VERSION 5.7 ;
  NOWIREEXTENSIONATPIN ON ;
  DIVIDERCHAR "/" ;
  BUSBITCHARS "[]" ;
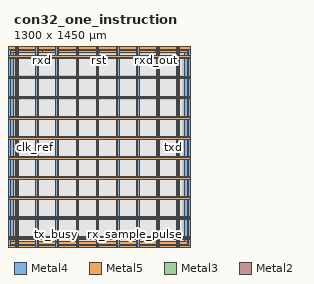
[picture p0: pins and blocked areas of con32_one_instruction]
MACRO con32_one_instruction
  CLASS BLOCK ;
  FOREIGN con32_one_instruction ;
  ORIGIN 0.000 0.000 ;
  SIZE 1300.000 BY 1450.000 ;
  PIN VDD
    DIRECTION INOUT ;
    USE POWER ;
    PORT
      LAYER Metal4 ;
        RECT -24.880 -18.160 -4.880 1464.640 ;
    END
    PORT
      LAYER Metal4 ;
        RECT 1304.640 -18.160 1324.640 1464.640 ;
    END
    PORT
      LAYER Metal5 ;
        RECT -24.880 -18.160 1324.640 1.840 ;
    END
    PORT
      LAYER Metal5 ;
        RECT -24.880 1444.640 1324.640 1464.640 ;
    END
    PORT
      LAYER Metal4 ;
        RECT 12.440 -42.960 22.440 1489.440 ;
    END
    PORT
      LAYER Metal4 ;
        RECT 166.040 -42.960 176.040 1489.440 ;
    END
    PORT
      LAYER Metal4 ;
        RECT 319.640 -42.960 329.640 1489.440 ;
    END
    PORT
      LAYER Metal4 ;
        RECT 473.240 -42.960 483.240 1489.440 ;
    END
    PORT
      LAYER Metal4 ;
        RECT 626.840 -42.960 636.840 1489.440 ;
    END
    PORT
      LAYER Metal4 ;
        RECT 780.440 -42.960 790.440 1489.440 ;
    END
    PORT
      LAYER Metal4 ;
        RECT 934.040 -42.960 944.040 1489.440 ;
    END
    PORT
      LAYER Metal4 ;
        RECT 1087.640 -42.960 1097.640 1489.440 ;
    END
    PORT
      LAYER Metal4 ;
        RECT 1241.240 -42.960 1251.240 1489.440 ;
    END
    PORT
      LAYER Metal5 ;
        RECT -49.680 19.490 1349.440 29.490 ;
    END
    PORT
      LAYER Metal5 ;
        RECT -49.680 172.670 1349.440 182.670 ;
    END
    PORT
      LAYER Metal5 ;
        RECT -49.680 325.850 1349.440 335.850 ;
    END
    PORT
      LAYER Metal5 ;
        RECT -49.680 479.030 1349.440 489.030 ;
    END
    PORT
      LAYER Metal5 ;
        RECT -49.680 632.210 1349.440 642.210 ;
    END
    PORT
      LAYER Metal5 ;
        RECT -49.680 785.390 1349.440 795.390 ;
    END
    PORT
      LAYER Metal5 ;
        RECT -49.680 938.570 1349.440 948.570 ;
    END
    PORT
      LAYER Metal5 ;
        RECT -49.680 1091.750 1349.440 1101.750 ;
    END
    PORT
      LAYER Metal5 ;
        RECT -49.680 1244.930 1349.440 1254.930 ;
    END
    PORT
      LAYER Metal5 ;
        RECT -49.680 1398.110 1349.440 1408.110 ;
    END
  END VDD
  PIN VSS
    DIRECTION INOUT ;
    USE GROUND ;
    PORT
      LAYER Metal4 ;
        RECT -49.680 -42.960 -29.680 1489.440 ;
    END
    PORT
      LAYER Metal4 ;
        RECT 1329.440 -42.960 1349.440 1489.440 ;
    END
    PORT
      LAYER Metal5 ;
        RECT -49.680 -42.960 1349.440 -22.960 ;
    END
    PORT
      LAYER Metal5 ;
        RECT -49.680 1469.440 1349.440 1489.440 ;
    END
    PORT
      LAYER Metal4 ;
        RECT 24.140 -42.960 34.140 1489.440 ;
    END
    PORT
      LAYER Metal4 ;
        RECT 177.740 -42.960 187.740 1489.440 ;
    END
    PORT
      LAYER Metal4 ;
        RECT 331.340 -42.960 341.340 1489.440 ;
    END
    PORT
      LAYER Metal4 ;
        RECT 484.940 -42.960 494.940 1489.440 ;
    END
    PORT
      LAYER Metal4 ;
        RECT 638.540 -42.960 648.540 1489.440 ;
    END
    PORT
      LAYER Metal4 ;
        RECT 792.140 -42.960 802.140 1489.440 ;
    END
    PORT
      LAYER Metal4 ;
        RECT 945.740 -42.960 955.740 1489.440 ;
    END
    PORT
      LAYER Metal4 ;
        RECT 1099.340 -42.960 1109.340 1489.440 ;
    END
    PORT
      LAYER Metal4 ;
        RECT 1252.940 -42.960 1262.940 1489.440 ;
    END
    PORT
      LAYER Metal5 ;
        RECT -49.680 31.190 1349.440 41.190 ;
    END
    PORT
      LAYER Metal5 ;
        RECT -49.680 184.370 1349.440 194.370 ;
    END
    PORT
      LAYER Metal5 ;
        RECT -49.680 337.550 1349.440 347.550 ;
    END
    PORT
      LAYER Metal5 ;
        RECT -49.680 490.730 1349.440 500.730 ;
    END
    PORT
      LAYER Metal5 ;
        RECT -49.680 643.910 1349.440 653.910 ;
    END
    PORT
      LAYER Metal5 ;
        RECT -49.680 797.090 1349.440 807.090 ;
    END
    PORT
      LAYER Metal5 ;
        RECT -49.680 950.270 1349.440 960.270 ;
    END
    PORT
      LAYER Metal5 ;
        RECT -49.680 1103.450 1349.440 1113.450 ;
    END
    PORT
      LAYER Metal5 ;
        RECT -49.680 1256.630 1349.440 1266.630 ;
    END
    PORT
      LAYER Metal5 ;
        RECT -49.680 1409.810 1349.440 1419.810 ;
    END
  END VSS
  PIN clk_ref
    DIRECTION INPUT ;
    USE SIGNAL ;
    ANTENNAGATEAREA 2.352000 ;
    PORT
      LAYER Metal3 ;
        RECT 0.000 724.640 0.560 725.200 ;
    END
  END clk_ref
  PIN rst
    DIRECTION INPUT ;
    USE SIGNAL ;
    ANTENNAGATEAREA 0.666400 ;
    PORT
      LAYER Metal2 ;
        RECT 649.600 1449.440 650.160 1450.000 ;
    END
  END rst
  PIN rx_sample_pulse
    DIRECTION OUTPUT ;
    USE SIGNAL ;
    ANTENNADIFFAREA 1.237600 ;
    PORT
      LAYER Metal2 ;
        RECT 974.400 0.000 974.960 0.560 ;
    END
  END rx_sample_pulse
  PIN rxd
    DIRECTION INPUT ;
    USE SIGNAL ;
    ANTENNAGATEAREA 0.666400 ;
    PORT
      LAYER Metal2 ;
        RECT 216.160 1449.440 216.720 1450.000 ;
    END
  END rxd
  PIN rxd_out
    DIRECTION OUTPUT ;
    USE SIGNAL ;
    ANTENNADIFFAREA 1.237600 ;
    PORT
      LAYER Metal2 ;
        RECT 1083.040 1449.440 1083.600 1450.000 ;
    END
  END rxd_out
  PIN tx_busy
    DIRECTION OUTPUT ;
    USE SIGNAL ;
    ANTENNADIFFAREA 1.237600 ;
    PORT
      LAYER Metal2 ;
        RECT 324.800 0.000 325.360 0.560 ;
    END
  END tx_busy
  PIN txd
    DIRECTION OUTPUT ;
    USE SIGNAL ;
    ANTENNADIFFAREA 1.237600 ;
    PORT
      LAYER Metal3 ;
        RECT 1299.440 724.640 1300.000 725.200 ;
    END
  END txd
  OBS
      LAYER Nwell ;
        RECT 0.690 7.410 1299.070 1439.070 ;
      LAYER Metal1 ;
        RECT 1.120 7.540 1298.640 1438.940 ;
      LAYER Metal2 ;
        RECT 0.140 1449.140 215.860 1449.440 ;
        RECT 217.020 1449.140 649.300 1449.440 ;
        RECT 650.460 1449.140 1082.740 1449.440 ;
        RECT 1083.900 1449.140 1299.620 1449.440 ;
        RECT 0.140 0.860 1299.620 1449.140 ;
        RECT 0.140 0.090 324.500 0.860 ;
        RECT 325.660 0.090 974.100 0.860 ;
        RECT 975.260 0.090 1299.620 0.860 ;
      LAYER Metal3 ;
        RECT 0.090 725.500 1299.670 1438.780 ;
        RECT 0.860 724.340 1299.140 725.500 ;
        RECT 0.090 0.140 1299.670 724.340 ;
      LAYER Metal4 ;
        RECT 0.140 0.090 12.140 1437.430 ;
        RECT 22.740 0.090 23.840 1437.430 ;
        RECT 34.440 0.090 165.740 1437.430 ;
        RECT 176.340 0.090 177.440 1437.430 ;
        RECT 188.040 0.090 319.340 1437.430 ;
        RECT 329.940 0.090 331.040 1437.430 ;
        RECT 341.640 0.090 472.940 1437.430 ;
        RECT 483.540 0.090 484.640 1437.430 ;
        RECT 495.240 0.090 626.540 1437.430 ;
        RECT 637.140 0.090 638.240 1437.430 ;
        RECT 648.840 0.090 780.140 1437.430 ;
        RECT 790.740 0.090 791.840 1437.430 ;
        RECT 802.440 0.090 933.740 1437.430 ;
        RECT 944.340 0.090 945.440 1437.430 ;
        RECT 956.040 0.090 1087.340 1437.430 ;
        RECT 1097.940 0.090 1099.040 1437.430 ;
        RECT 1109.640 0.090 1240.940 1437.430 ;
        RECT 1251.540 0.090 1252.640 1437.430 ;
        RECT 1263.240 0.090 1295.700 1437.430 ;
      LAYER Metal5 ;
        RECT 2.300 1267.230 1285.140 1397.470 ;
        RECT 2.300 1255.530 1285.140 1256.030 ;
        RECT 2.300 1114.050 1285.140 1244.330 ;
        RECT 2.300 1102.350 1285.140 1102.850 ;
        RECT 2.300 960.870 1285.140 1091.150 ;
        RECT 2.300 949.170 1285.140 949.670 ;
        RECT 2.300 807.690 1285.140 937.970 ;
        RECT 2.300 795.990 1285.140 796.490 ;
        RECT 2.300 654.510 1285.140 784.790 ;
        RECT 2.300 642.810 1285.140 643.310 ;
        RECT 2.300 501.330 1285.140 631.610 ;
        RECT 2.300 489.630 1285.140 490.130 ;
        RECT 2.300 348.150 1285.140 478.430 ;
        RECT 2.300 336.450 1285.140 336.950 ;
        RECT 2.300 194.970 1285.140 325.250 ;
        RECT 2.300 183.270 1285.140 183.770 ;
        RECT 2.300 41.790 1285.140 172.070 ;
        RECT 2.300 30.090 1285.140 30.590 ;
        RECT 2.300 3.830 1285.140 18.890 ;
  END
END con32_one_instruction
END LIBRARY

